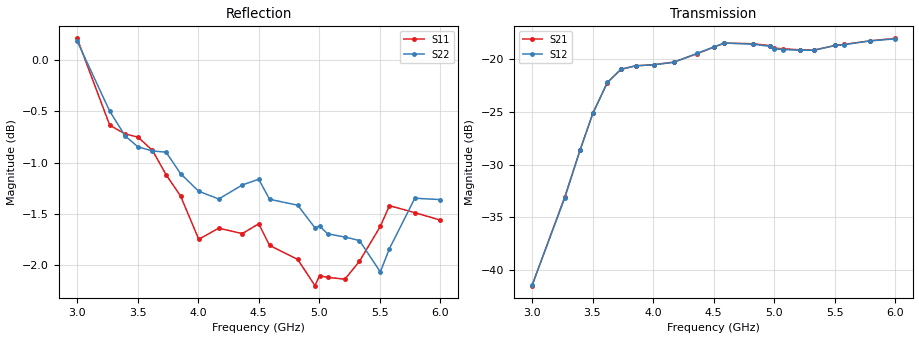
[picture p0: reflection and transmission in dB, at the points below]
!  26/11/2025  14:21:27
! Ref Plane: 0.000 mm
# MHZ S MA R  50
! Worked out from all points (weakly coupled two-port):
!   401 points, 3 GHz to 6 GHz, reference 50 ohm
!   highest |S21| = -18.04 dB at 6 GHz (marker M1); lowest = -41.5 dB at 3 GHz (marker M2)
!   lowest |S11| = -2.2 dB at 4.965 GHz (marker M3), VSWR 7.92, Z = 13.9 - j53.7 ohm
!   |S11| at or under -10 dB: nowhere
!   |S22| runs from -2.1 to 0.3 dB; largest |S21 - S12| = 0.0052
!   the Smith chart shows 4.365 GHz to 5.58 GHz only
!   S11 on the Smith chart (normalised r, x): 4.365 GHz: 0.15, +0.74; 4.59 GHz: 1.04, +2.84; 4.822 GHz: 0.90, -2.53; 5.07 GHz: 0.17, -0.63; 5.332 GHz: 0.11, +0.08; 5.58 GHz: 0.14, +0.83
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3000  1.025 -138.6  0.008442 51.3  0.008472 53.1  1.022 -105.5
3270  0.9294 151.5  0.0222 -17.2  0.02194 -14.9  0.9441 -171.4
3397.5  0.9204 108.2  0.03707 -58.1  0.03718 -56.8  0.9183 149.7
3502.5  0.9171 65.4  0.05535 -99.0  0.05527 -97.7  0.9071 111.7
3622.5  0.9035 14.6  0.07741 -151.3  0.07745 -149.9  0.9029 59.9
3735  0.8791 -34.3  0.08938 158.9  0.08957 160.5  0.9017 10.5
3855  0.8582 -82.3  0.09283 110.3  0.09291 112.0  0.8801 -38.4
4005  0.8174 -136.3  0.09404 57.5  0.09393 58.8  0.8628 -90.7
4170  0.8277 169.0  0.09664 4.6  0.09648 6.4  0.8554 -142.6
4365  0.8227 106.4  0.106 -55.5  0.1065 -53.6  0.869 158.8
4500  0.8318 63.4  0.1138 -98.6  0.114 -97.0  0.8746 117.0
4590  0.8118 34.9  0.119 -127.7  0.1191 -126.6  0.8551 88.2
4822.5  0.7991 -39.2  0.1182 158.6  0.1176 160.1  0.8494 18.3
4965  0.7758 -83.9  0.1158 115.7  0.1149 117.2  0.828 -22.5
5002.5  0.7845 -95.7  0.1126 105.2  0.1117 106.4  0.8298 -34.0
5070  0.7831 -114.8  0.1118 86.3  0.1109 87.4  0.8224 -53.4
5212.5  0.7815 -156.3  0.1106 47.0  0.1101 48.2  0.8195 -92.2
5332.5  0.7974 170.2  0.1104 14.6  0.1101 15.9  0.8163 -127.6
5505  0.8294 119.9  0.116 -33.4  0.116 -31.2  0.7879 -176.7
5580  0.849 100.1  0.1174 -53.9  0.117 -51.9  0.8088 161.6
5790  0.8423 40.7  0.1219 -113.8  0.1219 -111.5  0.8561 103.8
6000  0.8353 -19.8  0.1253 -173.1  0.1246 -171.5  0.8548 50.5
